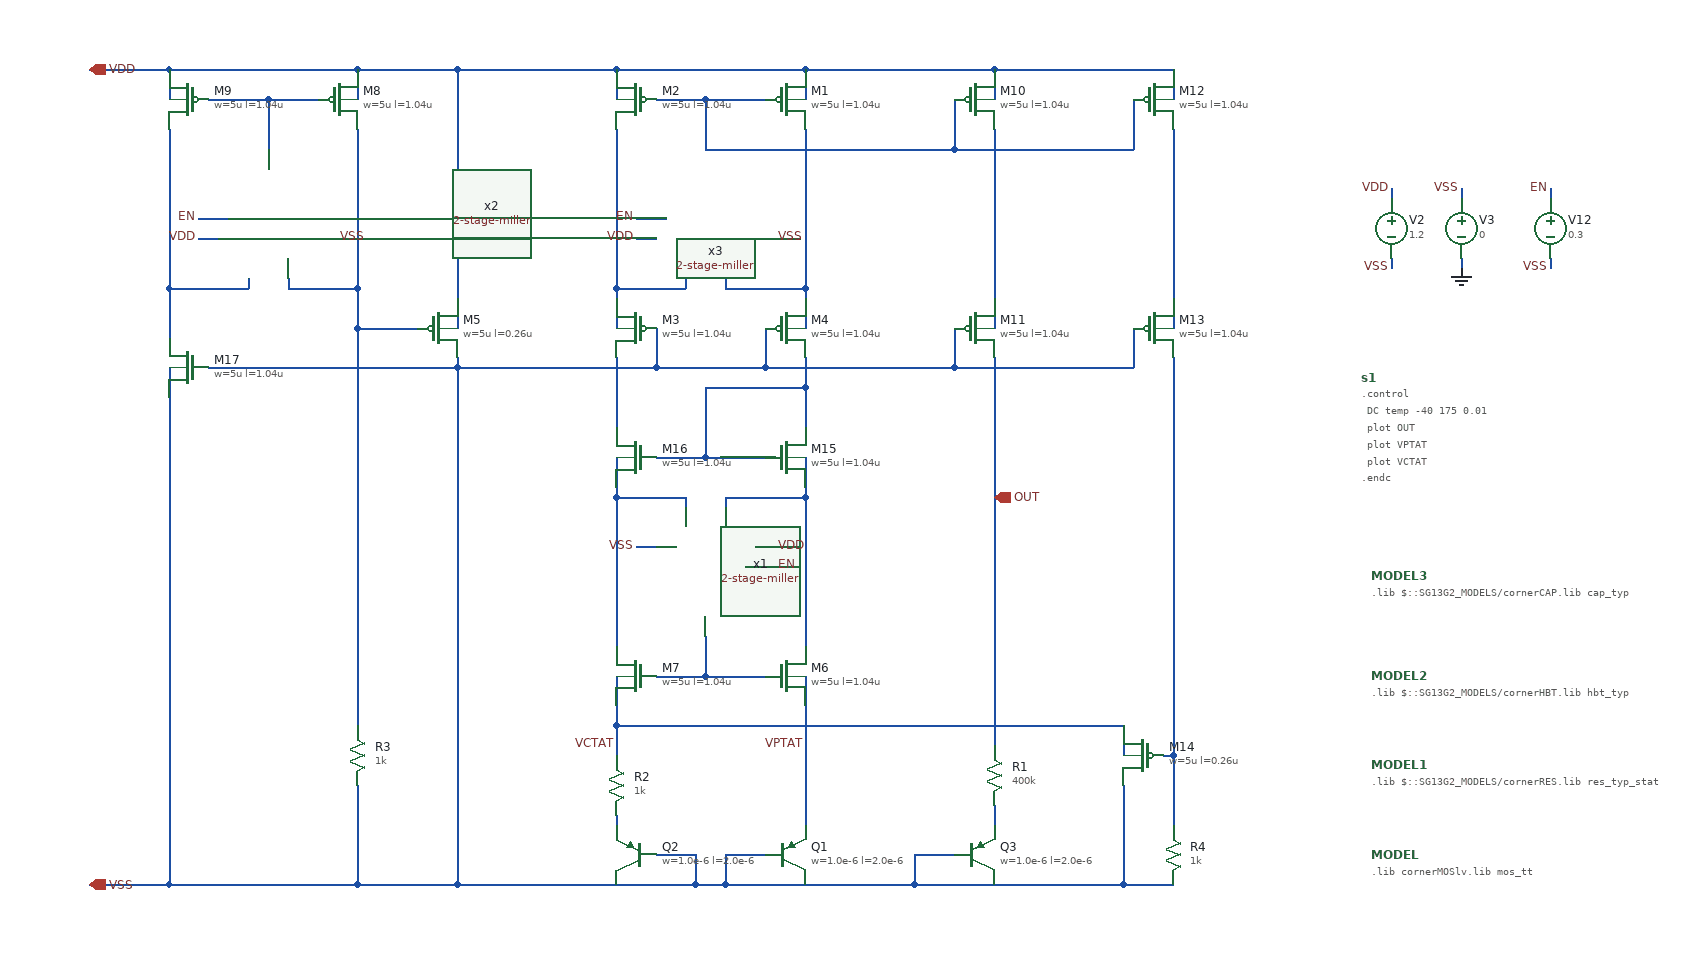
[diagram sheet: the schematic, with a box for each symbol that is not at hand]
v {xschem version=3.4.7 file_version=1.2}
G {}
K {}
V {}
S {}
E {}
N 710 -550 710 -480 {lab=#net1}
N 710 -480 780 -480 {lab=#net1}
N 710 -550 810 -550 {lab=#net1}
N 810 -580 810 -550 {lab=#net1}
N 960 -570 1140 -570 {lab=VSS}
N 1140 -610 1140 -570 {lab=VSS}
N 960 -610 960 -570 {lab=VSS}
N 770 -570 960 -570 {lab=VSS}
N 770 -610 770 -570 {lab=VSS}
N 660 -570 770 -570 {lab=VSS}
N 660 -610 660 -570 {lab=VSS}
N 1000 -870 1180 -870 {lab=VDD}
N 620 -650 620 -610 {lab=#net2}
N 810 -650 810 -610 {lab=#net3}
N 1180 -870 1180 -840 {lab=VDD}
N 1000 -870 1000 -840 {lab=VDD}
N 810 -870 1000 -870 {lab=VDD}
N 810 -870 810 -840 {lab=VDD}
N 620 -870 810 -870 {lab=VDD}
N 620 -870 620 -840 {lab=VDD}
N 710 -840 770 -840 {lab=#net4}
N 660 -840 710 -840 {lab=#net4}
N 710 -840 710 -790 {lab=#net4}
N 1140 -840 1140 -790 {lab=#net4}
N 960 -840 960 -790 {lab=#net4}
N 620 -210 620 -180 {lab=VCTAT}
N 620 -210 1130 -210 {lab=VCTAT}
N 1180 -180 1180 -110 {lab=#net5}
N 1170 -180 1180 -180 {lab=#net5}
N 1130 -210 1130 -180 {lab=VCTAT}
N 620 -580 620 -510 {lab=#net6}
N 810 -550 810 -510 {lab=#net1}
N 710 -260 770 -260 {lab=#net7}
N 620 -260 620 -210 {lab=VCTAT}
N 810 -260 810 -110 {lab=VPTAT}
N 1000 -130 1000 -110 {lab=#net8}
N 1130 -50 1180 -50 {lab=VSS}
N 660 -80 700 -80 {lab=VSS}
N 700 -80 700 -50 {lab=VSS}
N 730 -80 770 -80 {lab=VSS}
N 730 -80 730 -50 {lab=VSS}
N 700 -50 730 -50 {lab=VSS}
N 920 -80 960 -80 {lab=VSS}
N 920 -80 920 -50 {lab=VSS}
N 730 -50 920 -50 {lab=VSS}
N 1130 -150 1130 -50 {lab=VSS}
N 920 -50 1130 -50 {lab=VSS}
N 460 -570 660 -570 {lab=VSS}
N 460 -580 460 -570 {lab=VSS}
N 460 -50 700 -50 {lab=VSS}
N 620 -120 620 -110 {lab=#net9}
N 710 -790 960 -790 {lab=#net4}
N 960 -790 1140 -790 {lab=#net4}
N 690 -660 690 -650 {lab=#net2}
N 620 -650 690 -650 {lab=#net2}
N 730 -660 730 -650 {lab=#net3}
N 730 -650 810 -650 {lab=#net3}
N 620 -810 620 -650 {lab=#net2}
N 810 -810 810 -650 {lab=#net3}
N 460 -870 460 -610 {lab=VDD}
N 460 -870 620 -870 {lab=VDD}
N 1180 -810 1180 -610 {lab=#net10}
N 1000 -810 1000 -610 {lab=#net11}
N 660 -480 710 -480 {lab=#net1}
N 460 -570 460 -50 {lab=VSS}
N 810 -440 810 -290 {lab=#net12}
N 620 -440 620 -290 {lab=#net13}
N 1000 -580 1000 -190 {lab=OUT}
N 1180 -580 1180 -180 {lab=#net5}
N 730 -440 730 -430 {lab=#net12}
N 730 -440 810 -440 {lab=#net12}
N 810 -480 810 -440 {lab=#net12}
N 690 -440 690 -430 {lab=#net13}
N 620 -440 690 -440 {lab=#net13}
N 620 -480 620 -440 {lab=#net13}
N 710 -300 710 -260 {lab=#net7}
N 660 -260 710 -260 {lab=#net7}
N 760 -390 780 -390 {lab=VDD}
N 640 -390 660 -390 {lab=VSS}
N 750 -370 780 -370 {lab=EN}
N 640 -720 670 -720 {lab=EN}
N 640 -700 660 -700 {lab=VDD}
N 760 -700 780 -700 {lab=VSS}
N 1560 -680 1560 -670 {lab=VSS}
N 1560 -750 1560 -740 {lab=EN}
N 1400 -750 1400 -740 {lab=VDD}
N 1400 -680 1400 -670 {lab=VSS}
N 1470 -680 1470 -670 {lab=GND}
N 1470 -750 1470 -740 {lab=VSS}
N 360 -870 360 -840 {lab=VDD}
N 170 -870 360 -870 {lab=VDD}
N 170 -870 170 -840 {lab=VDD}
N 360 -870 460 -870 {lab=VDD}
N 210 -570 460 -570 {lab=VSS}
N 170 -570 170 -50 {lab=VSS}
N 170 -650 170 -600 {lab=#net14}
N 360 -610 360 -210 {lab=#net15}
N 90 -870 170 -870 {lab=VDD}
N 360 -50 460 -50 {lab=VSS}
N 90 -50 170 -50 {lab=VSS}
N 170 -50 360 -50 {lab=VSS}
N 360 -610 420 -610 {lab=#net15}
N 360 -650 360 -610 {lab=#net15}
N 360 -150 360 -50 {lab=VSS}
N 320 -700 340 -700 {lab=VSS}
N 200 -700 220 -700 {lab=VDD}
N 250 -660 250 -650 {lab=#net14}
N 170 -650 250 -650 {lab=#net14}
N 290 -660 290 -650 {lab=#net15}
N 290 -650 360 -650 {lab=#net15}
N 200 -720 230 -720 {lab=EN}
N 360 -810 360 -650 {lab=#net15}
N 270 -840 320 -840 {lab=#net16}
N 170 -810 170 -650 {lab=#net14}
N 270 -840 270 -790 {lab=#net16}
N 210 -840 270 -840 {lab=#net16}
C {sg13g2_pr/sg13_lv_pmos.sym} 790 -840 0 0 {name=M1
l=1.04u
w=5u
ng=1
m=4
model=sg13_lv_pmos
spiceprefix=X
}
C {sg13g2_pr/sg13_lv_pmos.sym} 640 -840 0 1 {name=M2
l=1.04u
w=5u
ng=1
m=4
model=sg13_lv_pmos
spiceprefix=X
}
C {sg13g2_pr/sg13_lv_pmos.sym} 640 -610 0 1 {name=M3
l=1.04u
w=5u
ng=1
m=4
model=sg13_lv_pmos
spiceprefix=X
}
C {sg13g2_pr/sg13_lv_pmos.sym} 790 -610 0 0 {name=M4
l=1.04u
w=5u
ng=1
m=4
model=sg13_lv_pmos
spiceprefix=X
}
C {sg13g2_pr/sg13_lv_pmos.sym} 440 -610 0 0 {name=M5
l=0.26u
w=5u
ng=1
m=2
model=sg13_lv_pmos
spiceprefix=X
}
C {sg13g2_pr/sg13_lv_pmos.sym} 980 -840 0 0 {name=M10
l=1.04u
w=5u
ng=1
m=4
model=sg13_lv_pmos
spiceprefix=X
}
C {sg13g2_pr/sg13_lv_pmos.sym} 980 -610 0 0 {name=M11
l=1.04u
w=5u
ng=1
m=4
model=sg13_lv_pmos
spiceprefix=X
}
C {sg13g2_pr/sg13_lv_pmos.sym} 1160 -840 0 0 {name=M12
l=1.04u
w=5u
ng=1
m=4
model=sg13_lv_pmos
spiceprefix=X
}
C {sg13g2_pr/sg13_lv_pmos.sym} 1160 -610 0 0 {name=M13
l=1.04u
w=5u
ng=1
m=4
model=sg13_lv_pmos
spiceprefix=X
}
C {sg13g2_pr/pnpMPA.sym} 790 -80 0 0 {name=Q1
model=pnpMPA
spiceprefix=X
w=1.0e-6
l=2.0e-6
m=1
}
C {sg13g2_pr/pnpMPA.sym} 640 -80 0 1 {name=Q2
model=pnpMPA
spiceprefix=X
w=1.0e-6
l=2.0e-6
m=8
}
C {sg13g2_pr/pnpMPA.sym} 980 -80 0 0 {name=Q3
model=pnpMPA
spiceprefix=X
w=1.0e-6
l=2.0e-6
m=1
}
C {sg13g2_pr/sg13_lv_pmos.sym} 1150 -180 0 1 {name=M14
l=0.26u
w=5u
ng=1
m=2
model=sg13_lv_pmos
spiceprefix=X
}
C {sg13g2_pr/sg13_lv_nmos.sym} 790 -480 0 0 {name=M15
l=1.04u
w=5u
ng=1
m=2
model=sg13_lv_nmos
spiceprefix=X
}
C {sg13g2_pr/sg13_lv_nmos.sym} 640 -480 0 1 {name=M16
l=1.04u
w=5u
ng=1
m=2
model=sg13_lv_nmos
spiceprefix=X
}
C {sg13g2_pr/sg13_lv_nmos.sym} 790 -260 0 0 {name=M6
l=1.04u
w=5u
ng=1
m=2
model=sg13_lv_nmos
spiceprefix=X
}
C {sg13g2_pr/sg13_lv_nmos.sym} 640 -260 0 1 {name=M7
l=1.04u
w=5u
ng=1
m=2
model=sg13_lv_nmos
spiceprefix=X
}
C {iopin.sym} 90 -870 0 1 {name=p1 lab=VDD}
C {iopin.sym} 90 -50 0 1 {name=p2 lab=VSS}
C {opin.sym} 1000 -440 0 0 {name=p3 lab=OUT}
C {res.sym} 1180 -80 0 0 {name=R4
value=1k
footprint=1206
device=resistor
m=1}
C {res.sym} 1000 -160 0 0 {name=R1
value=400k
footprint=1206
device=resistor
m=1}
C {res.sym} 620 -150 0 0 {name=R2
value=1k
footprint=1206
device=resistor
m=1}
C {lab_pin.sym} 620 -190 0 0 {name=p7 sig_type=std_logic lab=VCTAT}
C {lab_pin.sym} 810 -190 0 0 {name=p8 sig_type=std_logic lab=VPTAT}
C {bandgap-ota-ihp/libs/core_analog/core_ota/schematics/2-stage-miller.sym} 910 -510 3 0 {name=x1}
C {bandgap-ota-ihp/libs/core_analog/core_ota/schematics/2-stage-miller.sym} 510 -580 1 0 {name=x2}
C {lab_pin.sym} 640 -390 0 0 {name=p4 sig_type=std_logic lab=VSS}
C {lab_pin.sym} 780 -390 0 1 {name=p5 sig_type=std_logic lab=VDD}
C {lab_pin.sym} 780 -370 0 1 {name=p6 sig_type=std_logic lab=EN}
C {lab_pin.sym} 780 -700 0 1 {name=p9 sig_type=std_logic lab=VSS}
C {lab_pin.sym} 640 -700 0 0 {name=p10 sig_type=std_logic lab=VDD}
C {lab_pin.sym} 640 -720 0 0 {name=p11 sig_type=std_logic lab=EN}
C {vsource.sym} 1560 -710 0 0 {name=V12 value=0.3 savecurrent=false}
C {lab_pin.sym} 1560 -750 0 0 {name=p20 sig_type=std_logic lab=EN}
C {lab_pin.sym} 1560 -670 0 0 {name=p21 sig_type=std_logic lab=VSS}
C {vsource.sym} 1400 -710 0 0 {name=V2 value=1.2 savecurrent=false}
C {vsource.sym} 1470 -710 0 0 {name=V3 value=0 savecurrent=false}
C {lab_pin.sym} 1400 -750 0 0 {name=p14 sig_type=std_logic lab=VDD}
C {lab_pin.sym} 1400 -670 0 0 {name=p15 sig_type=std_logic lab=VSS}
C {lab_pin.sym} 1470 -750 0 0 {name=p16 sig_type=std_logic lab=VSS}
C {gnd.sym} 1470 -670 0 0 {name=l1 lab=GND}
C {code_shown.sym} 1370 -560 0 0 {name=s1 only_toplevel=false value="

.control
	DC temp -40 175 0.01
	plot OUT
	plot VPTAT
	plot VCTAT
.endc
"}
C {devices/code_shown.sym} 1380 -80 0 0 {name=MODEL only_toplevel=true
format="tcleval( @value )"
value=".lib cornerMOSlv.lib mos_tt
"}
C {devices/code_shown.sym} 1380 -170 0 0 {name=MODEL1 only_toplevel=true
format="tcleval( @value )"
value="
.lib $::SG13G2_MODELS/cornerRES.lib res_typ_stat
"}
C {devices/code_shown.sym} 1380 -260 0 0 {name=MODEL2 only_toplevel=true
format="tcleval( @value )"
value="
.lib $::SG13G2_MODELS/cornerHBT.lib hbt_typ
"}
C {devices/code_shown.sym} 1380 -360 0 0 {name=MODEL3 only_toplevel=true
format="tcleval( @value )"
value="
.lib $::SG13G2_MODELS/cornerCAP.lib cap_typ
"}
C {sg13g2_pr/sg13_lv_pmos.sym} 340 -840 0 0 {name=M8
l=1.04u
w=5u
ng=1
m=4
model=sg13_lv_pmos
spiceprefix=X
}
C {sg13g2_pr/sg13_lv_pmos.sym} 190 -840 0 1 {name=M9
l=1.04u
w=5u
ng=1
m=4
model=sg13_lv_pmos
spiceprefix=X
}
C {sg13g2_pr/sg13_lv_nmos.sym} 190 -570 0 1 {name=M17
l=1.04u
w=5u
ng=1
m=2
model=sg13_lv_nmos
spiceprefix=X
}
C {res.sym} 360 -180 0 0 {name=R3
value=1k
footprint=1206
device=resistor
m=1}
C {bandgap-ota-ihp/libs/core_analog/core_ota/schematics/2-stage-miller.sym} 470 -510 3 0 {name=x3}
C {lab_pin.sym} 200 -700 0 0 {name=p17 sig_type=std_logic lab=VDD}
C {lab_pin.sym} 340 -700 0 1 {name=p18 sig_type=std_logic lab=VSS}
C {lab_pin.sym} 200 -720 0 0 {name=p19 sig_type=std_logic lab=EN}
